VERSION 5.7 ;
  NOWIREEXTENSIONATPIN ON ;
  DIVIDERCHAR "/" ;
  BUSBITCHARS "[]" ;
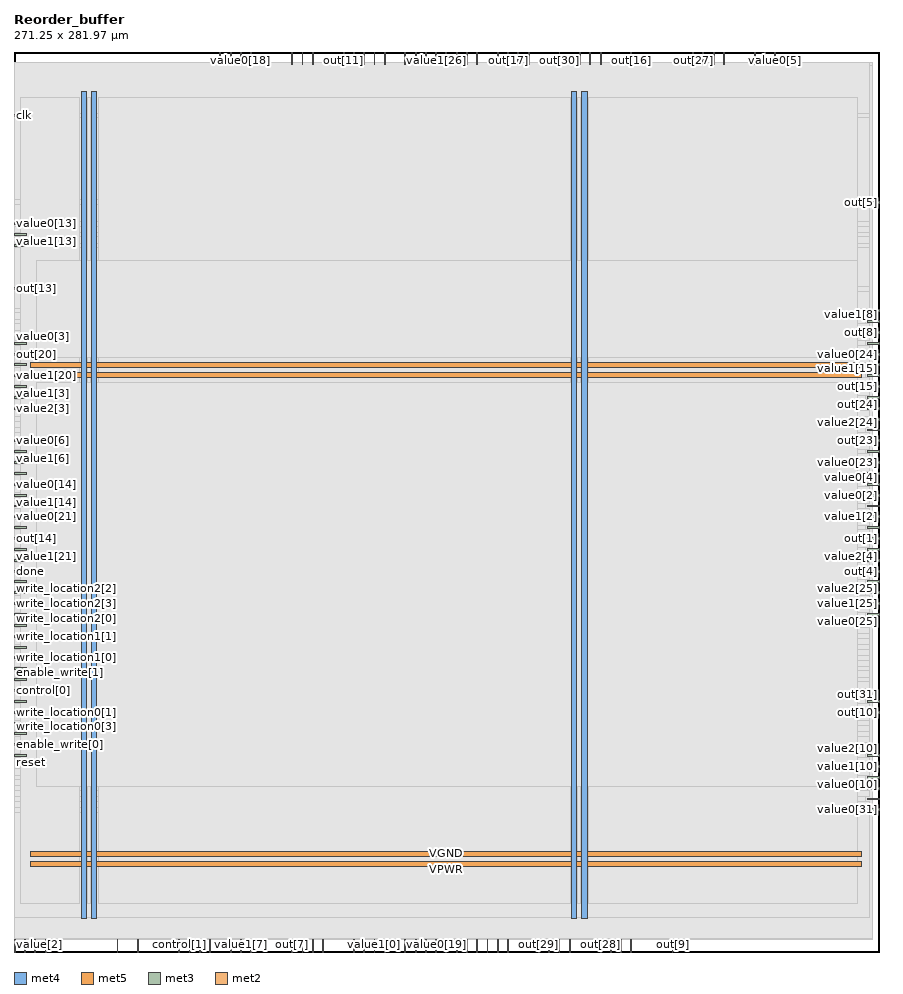
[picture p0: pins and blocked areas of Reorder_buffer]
MACRO Reorder_buffer
  CLASS BLOCK ;
  FOREIGN Reorder_buffer ;
  ORIGIN 0.000 0.000 ;
  SIZE 271.250 BY 281.970 ;
  PIN VGND
    DIRECTION INOUT ;
    USE GROUND ;
    PORT
      LAYER met4 ;
        RECT 24.340 10.640 25.940 269.520 ;
    END
    PORT
      LAYER met4 ;
        RECT 177.940 10.640 179.540 269.520 ;
    END
    PORT
      LAYER met5 ;
        RECT 5.280 30.030 265.660 31.630 ;
    END
    PORT
      LAYER met5 ;
        RECT 5.280 183.210 265.660 184.810 ;
    END
  END VGND
  PIN VPWR
    DIRECTION INOUT ;
    USE POWER ;
    PORT
      LAYER met4 ;
        RECT 21.040 10.640 22.640 269.520 ;
    END
    PORT
      LAYER met4 ;
        RECT 174.640 10.640 176.240 269.520 ;
    END
    PORT
      LAYER met5 ;
        RECT 5.280 26.730 265.660 28.330 ;
    END
    PORT
      LAYER met5 ;
        RECT 5.280 179.910 265.660 181.510 ;
    END
  END VPWR
  PIN clk
    DIRECTION INPUT ;
    USE SIGNAL ;
    ANTENNAGATEAREA 0.852000 ;
    PORT
      LAYER met3 ;
        RECT 0.000 261.840 4.000 262.440 ;
    END
  END clk
  PIN control[0]
    DIRECTION INPUT ;
    USE SIGNAL ;
    ANTENNAGATEAREA 0.196500 ;
    PORT
      LAYER met3 ;
        RECT 0.000 81.640 4.000 82.240 ;
    END
  END control[0]
  PIN control[1]
    DIRECTION INPUT ;
    USE SIGNAL ;
    ANTENNAGATEAREA 0.196500 ;
    PORT
      LAYER met2 ;
        RECT 51.610 0.000 51.890 4.000 ;
    END
  END control[1]
  PIN data_location[0]
    DIRECTION OUTPUT ;
    USE SIGNAL ;
    ANTENNADIFFAREA 0.445500 ;
    PORT
      LAYER met2 ;
        RECT 38.730 0.000 39.010 4.000 ;
    END
  END data_location[0]
  PIN data_location[1]
    DIRECTION OUTPUT ;
    USE SIGNAL ;
    ANTENNADIFFAREA 0.445500 ;
    PORT
      LAYER met2 ;
        RECT 58.050 0.000 58.330 4.000 ;
    END
  END data_location[1]
  PIN data_location[2]
    DIRECTION OUTPUT ;
    USE SIGNAL ;
    ANTENNADIFFAREA 0.445500 ;
    PORT
      LAYER met2 ;
        RECT 32.290 0.000 32.570 4.000 ;
    END
  END data_location[2]
  PIN data_location[3]
    DIRECTION OUTPUT ;
    USE SIGNAL ;
    ANTENNADIFFAREA 0.445500 ;
    PORT
      LAYER met2 ;
        RECT 61.270 0.000 61.550 4.000 ;
    END
  END data_location[3]
  PIN done
    DIRECTION OUTPUT ;
    USE SIGNAL ;
    ANTENNADIFFAREA 0.445500 ;
    PORT
      LAYER met3 ;
        RECT 0.000 119.040 4.000 119.640 ;
    END
  END done
  PIN enable_write[0]
    DIRECTION INPUT ;
    USE SIGNAL ;
    ANTENNAGATEAREA 0.196500 ;
    PORT
      LAYER met3 ;
        RECT 0.000 64.640 4.000 65.240 ;
    END
  END enable_write[0]
  PIN enable_write[1]
    DIRECTION INPUT ;
    USE SIGNAL ;
    ANTENNAGATEAREA 0.196500 ;
    PORT
      LAYER met3 ;
        RECT 0.000 85.040 4.000 85.640 ;
    END
  END enable_write[1]
  PIN enable_write[2]
    DIRECTION INPUT ;
    USE SIGNAL ;
    ANTENNAGATEAREA 0.196500 ;
    PORT
      LAYER met3 ;
        RECT 0.000 112.240 4.000 112.840 ;
    END
  END enable_write[2]
  PIN out[0]
    DIRECTION OUTPUT ;
    USE SIGNAL ;
    ANTENNADIFFAREA 0.445500 ;
    PORT
      LAYER met2 ;
        RECT 125.670 0.000 125.950 4.000 ;
    END
  END out[0]
  PIN out[10]
    DIRECTION OUTPUT ;
    USE SIGNAL ;
    ANTENNADIFFAREA 0.445500 ;
    PORT
      LAYER met3 ;
        RECT 267.250 74.840 271.250 75.440 ;
    END
  END out[10]
  PIN out[11]
    DIRECTION OUTPUT ;
    USE SIGNAL ;
    ANTENNADIFFAREA 0.445500 ;
    PORT
      LAYER met2 ;
        RECT 103.130 277.970 103.410 281.970 ;
    END
  END out[11]
  PIN out[12]
    DIRECTION OUTPUT ;
    USE SIGNAL ;
    ANTENNADIFFAREA 0.445500 ;
    PORT
      LAYER met2 ;
        RECT 122.450 277.970 122.730 281.970 ;
    END
  END out[12]
  PIN out[13]
    DIRECTION OUTPUT ;
    USE SIGNAL ;
    ANTENNADIFFAREA 0.445500 ;
    PORT
      LAYER met3 ;
        RECT 0.000 207.440 4.000 208.040 ;
    END
  END out[13]
  PIN out[14]
    DIRECTION OUTPUT ;
    USE SIGNAL ;
    ANTENNADIFFAREA 0.445500 ;
    PORT
      LAYER met3 ;
        RECT 0.000 129.240 4.000 129.840 ;
    END
  END out[14]
  PIN out[15]
    DIRECTION OUTPUT ;
    USE SIGNAL ;
    ANTENNADIFFAREA 0.445500 ;
    PORT
      LAYER met3 ;
        RECT 267.250 176.840 271.250 177.440 ;
    END
  END out[15]
  PIN out[16]
    DIRECTION OUTPUT ;
    USE SIGNAL ;
    ANTENNADIFFAREA 0.445500 ;
    PORT
      LAYER met2 ;
        RECT 193.290 277.970 193.570 281.970 ;
    END
  END out[16]
  PIN out[17]
    DIRECTION OUTPUT ;
    USE SIGNAL ;
    ANTENNADIFFAREA 0.445500 ;
    PORT
      LAYER met2 ;
        RECT 154.650 277.970 154.930 281.970 ;
    END
  END out[17]
  PIN out[18]
    DIRECTION OUTPUT ;
    USE SIGNAL ;
    ANTENNADIFFAREA 0.445500 ;
    PORT
      LAYER met2 ;
        RECT 74.150 277.970 74.430 281.970 ;
    END
  END out[18]
  PIN out[19]
    DIRECTION OUTPUT ;
    USE SIGNAL ;
    ANTENNADIFFAREA 0.445500 ;
    PORT
      LAYER met2 ;
        RECT 148.210 0.000 148.490 4.000 ;
    END
  END out[19]
  PIN out[1]
    DIRECTION OUTPUT ;
    USE SIGNAL ;
    ANTENNADIFFAREA 0.445500 ;
    PORT
      LAYER met3 ;
        RECT 267.250 129.240 271.250 129.840 ;
    END
  END out[1]
  PIN out[20]
    DIRECTION OUTPUT ;
    USE SIGNAL ;
    ANTENNADIFFAREA 0.445500 ;
    PORT
      LAYER met3 ;
        RECT 0.000 187.040 4.000 187.640 ;
    END
  END out[20]
  PIN out[21]
    DIRECTION OUTPUT ;
    USE SIGNAL ;
    ANTENNADIFFAREA 0.445500 ;
    PORT
      LAYER met3 ;
        RECT 0.000 132.640 4.000 133.240 ;
    END
  END out[21]
  PIN out[22]
    DIRECTION OUTPUT ;
    USE SIGNAL ;
    ANTENNADIFFAREA 0.445500 ;
    PORT
      LAYER met2 ;
        RECT 106.350 0.000 106.630 4.000 ;
    END
  END out[22]
  PIN out[23]
    DIRECTION OUTPUT ;
    USE SIGNAL ;
    ANTENNADIFFAREA 0.445500 ;
    PORT
      LAYER met3 ;
        RECT 267.250 159.840 271.250 160.440 ;
    END
  END out[23]
  PIN out[24]
    DIRECTION OUTPUT ;
    USE SIGNAL ;
    ANTENNADIFFAREA 0.445500 ;
    PORT
      LAYER met3 ;
        RECT 267.250 173.440 271.250 174.040 ;
    END
  END out[24]
  PIN out[25]
    DIRECTION OUTPUT ;
    USE SIGNAL ;
    ANTENNADIFFAREA 0.445500 ;
    PORT
      LAYER met3 ;
        RECT 267.250 112.240 271.250 112.840 ;
    END
  END out[25]
  PIN out[26]
    DIRECTION OUTPUT ;
    USE SIGNAL ;
    ANTENNADIFFAREA 0.445500 ;
    PORT
      LAYER met2 ;
        RECT 144.990 277.970 145.270 281.970 ;
    END
  END out[26]
  PIN out[27]
    DIRECTION OUTPUT ;
    USE SIGNAL ;
    ANTENNADIFFAREA 0.445500 ;
    PORT
      LAYER met2 ;
        RECT 212.610 277.970 212.890 281.970 ;
    END
  END out[27]
  PIN out[28]
    DIRECTION OUTPUT ;
    USE SIGNAL ;
    ANTENNADIFFAREA 0.445500 ;
    PORT
      LAYER met2 ;
        RECT 183.630 0.000 183.910 4.000 ;
    END
  END out[28]
  PIN out[29]
    DIRECTION OUTPUT ;
    USE SIGNAL ;
    ANTENNADIFFAREA 0.445500 ;
    PORT
      LAYER met2 ;
        RECT 164.310 0.000 164.590 4.000 ;
    END
  END out[29]
  PIN out[2]
    DIRECTION OUTPUT ;
    USE SIGNAL ;
    ANTENNADIFFAREA 0.445500 ;
    PORT
      LAYER met3 ;
        RECT 267.250 132.640 271.250 133.240 ;
    END
  END out[2]
  PIN out[30]
    DIRECTION OUTPUT ;
    USE SIGNAL ;
    ANTENNADIFFAREA 0.445500 ;
    PORT
      LAYER met2 ;
        RECT 170.750 277.970 171.030 281.970 ;
    END
  END out[30]
  PIN out[31]
    DIRECTION OUTPUT ;
    USE SIGNAL ;
    ANTENNADIFFAREA 0.445500 ;
    PORT
      LAYER met3 ;
        RECT 267.250 78.240 271.250 78.840 ;
    END
  END out[31]
  PIN out[3]
    DIRECTION OUTPUT ;
    USE SIGNAL ;
    ANTENNADIFFAREA 0.445500 ;
    PORT
      LAYER met2 ;
        RECT 106.350 277.970 106.630 281.970 ;
    END
  END out[3]
  PIN out[4]
    DIRECTION OUTPUT ;
    USE SIGNAL ;
    ANTENNADIFFAREA 0.445500 ;
    PORT
      LAYER met3 ;
        RECT 267.250 119.040 271.250 119.640 ;
    END
  END out[4]
  PIN out[5]
    DIRECTION OUTPUT ;
    USE SIGNAL ;
    ANTENNADIFFAREA 0.445500 ;
    PORT
      LAYER met3 ;
        RECT 267.250 234.640 271.250 235.240 ;
    END
  END out[5]
  PIN out[6]
    DIRECTION OUTPUT ;
    USE SIGNAL ;
    ANTENNADIFFAREA 0.445500 ;
    PORT
      LAYER met3 ;
        RECT 0.000 149.640 4.000 150.240 ;
    END
  END out[6]
  PIN out[7]
    DIRECTION OUTPUT ;
    USE SIGNAL ;
    ANTENNADIFFAREA 0.445500 ;
    PORT
      LAYER met2 ;
        RECT 87.030 0.000 87.310 4.000 ;
    END
  END out[7]
  PIN out[8]
    DIRECTION OUTPUT ;
    USE SIGNAL ;
    ANTENNADIFFAREA 0.445500 ;
    PORT
      LAYER met3 ;
        RECT 267.250 193.840 271.250 194.440 ;
    END
  END out[8]
  PIN out[9]
    DIRECTION OUTPUT ;
    USE SIGNAL ;
    ANTENNADIFFAREA 0.445500 ;
    PORT
      LAYER met2 ;
        RECT 206.170 0.000 206.450 4.000 ;
    END
  END out[9]
  PIN reset
    DIRECTION INPUT ;
    USE SIGNAL ;
    ANTENNAGATEAREA 0.196500 ;
    PORT
      LAYER met3 ;
        RECT 0.000 61.240 4.000 61.840 ;
    END
  END reset
  PIN success
    DIRECTION OUTPUT ;
    USE SIGNAL ;
    ANTENNADIFFAREA 0.445500 ;
    PORT
      LAYER met2 ;
        RECT 54.830 0.000 55.110 4.000 ;
    END
  END success
  PIN value0[0]
    DIRECTION INPUT ;
    USE SIGNAL ;
    ANTENNAGATEAREA 0.196500 ;
    PORT
      LAYER met2 ;
        RECT 109.570 0.000 109.850 4.000 ;
    END
  END value0[0]
  PIN value0[10]
    DIRECTION INPUT ;
    USE SIGNAL ;
    ANTENNAGATEAREA 0.196500 ;
    PORT
      LAYER met3 ;
        RECT 267.250 54.440 271.250 55.040 ;
    END
  END value0[10]
  PIN value0[11]
    DIRECTION INPUT ;
    USE SIGNAL ;
    ANTENNAGATEAREA 0.196500 ;
    PORT
      LAYER met2 ;
        RECT 90.250 277.970 90.530 281.970 ;
    END
  END value0[11]
  PIN value0[12]
    DIRECTION INPUT ;
    USE SIGNAL ;
    ANTENNAGATEAREA 0.196500 ;
    PORT
      LAYER met2 ;
        RECT 116.010 277.970 116.290 281.970 ;
    END
  END value0[12]
  PIN value0[13]
    DIRECTION INPUT ;
    USE SIGNAL ;
    ANTENNAGATEAREA 0.196500 ;
    PORT
      LAYER met3 ;
        RECT 0.000 227.840 4.000 228.440 ;
    END
  END value0[13]
  PIN value0[14]
    DIRECTION INPUT ;
    USE SIGNAL ;
    ANTENNAGATEAREA 0.196500 ;
    PORT
      LAYER met3 ;
        RECT 0.000 146.240 4.000 146.840 ;
    END
  END value0[14]
  PIN value0[15]
    DIRECTION INPUT ;
    USE SIGNAL ;
    ANTENNAGATEAREA 0.196500 ;
    PORT
      LAYER met3 ;
        RECT 267.250 183.640 271.250 184.240 ;
    END
  END value0[15]
  PIN value0[16]
    DIRECTION INPUT ;
    USE SIGNAL ;
    ANTENNAGATEAREA 0.196500 ;
    PORT
      LAYER met2 ;
        RECT 183.630 277.970 183.910 281.970 ;
    END
  END value0[16]
  PIN value0[17]
    DIRECTION INPUT ;
    USE SIGNAL ;
    ANTENNAGATEAREA 0.196500 ;
    PORT
      LAYER met2 ;
        RECT 141.770 277.970 142.050 281.970 ;
    END
  END value0[17]
  PIN value0[18]
    DIRECTION INPUT ;
    USE SIGNAL ;
    ANTENNAGATEAREA 0.196500 ;
    PORT
      LAYER met2 ;
        RECT 70.930 277.970 71.210 281.970 ;
    END
  END value0[18]
  PIN value0[19]
    DIRECTION INPUT ;
    USE SIGNAL ;
    ANTENNAGATEAREA 0.196500 ;
    PORT
      LAYER met2 ;
        RECT 132.110 0.000 132.390 4.000 ;
    END
  END value0[19]
  PIN value0[1]
    DIRECTION INPUT ;
    USE SIGNAL ;
    ANTENNAGATEAREA 0.196500 ;
    PORT
      LAYER met2 ;
        RECT 122.450 0.000 122.730 4.000 ;
    END
  END value0[1]
  PIN value0[20]
    DIRECTION INPUT ;
    USE SIGNAL ;
    ANTENNAGATEAREA 0.196500 ;
    PORT
      LAYER met3 ;
        RECT 0.000 183.640 4.000 184.240 ;
    END
  END value0[20]
  PIN value0[21]
    DIRECTION INPUT ;
    USE SIGNAL ;
    ANTENNAGATEAREA 0.196500 ;
    PORT
      LAYER met3 ;
        RECT 0.000 136.040 4.000 136.640 ;
    END
  END value0[21]
  PIN value0[22]
    DIRECTION INPUT ;
    USE SIGNAL ;
    ANTENNAGATEAREA 0.196500 ;
    PORT
      LAYER met2 ;
        RECT 90.250 0.000 90.530 4.000 ;
    END
  END value0[22]
  PIN value0[23]
    DIRECTION INPUT ;
    USE SIGNAL ;
    ANTENNAGATEAREA 0.196500 ;
    PORT
      LAYER met3 ;
        RECT 267.250 153.040 271.250 153.640 ;
    END
  END value0[23]
  PIN value0[24]
    DIRECTION INPUT ;
    USE SIGNAL ;
    ANTENNAGATEAREA 0.196500 ;
    PORT
      LAYER met3 ;
        RECT 267.250 187.040 271.250 187.640 ;
    END
  END value0[24]
  PIN value0[25]
    DIRECTION INPUT ;
    USE SIGNAL ;
    ANTENNAGATEAREA 0.196500 ;
    PORT
      LAYER met3 ;
        RECT 267.250 105.440 271.250 106.040 ;
    END
  END value0[25]
  PIN value0[26]
    DIRECTION INPUT ;
    USE SIGNAL ;
    ANTENNAGATEAREA 0.196500 ;
    PORT
      LAYER met2 ;
        RECT 128.890 277.970 129.170 281.970 ;
    END
  END value0[26]
  PIN value0[27]
    DIRECTION INPUT ;
    USE SIGNAL ;
    ANTENNAGATEAREA 0.196500 ;
    PORT
      LAYER met2 ;
        RECT 222.270 277.970 222.550 281.970 ;
    END
  END value0[27]
  PIN value0[28]
    DIRECTION INPUT ;
    USE SIGNAL ;
    ANTENNAGATEAREA 0.196500 ;
    PORT
      LAYER met2 ;
        RECT 167.530 0.000 167.810 4.000 ;
    END
  END value0[28]
  PIN value0[29]
    DIRECTION INPUT ;
    USE SIGNAL ;
    ANTENNAGATEAREA 0.196500 ;
    PORT
      LAYER met2 ;
        RECT 144.990 0.000 145.270 4.000 ;
    END
  END value0[29]
  PIN value0[2]
    DIRECTION INPUT ;
    USE SIGNAL ;
    ANTENNAGATEAREA 0.196500 ;
    PORT
      LAYER met3 ;
        RECT 267.250 142.840 271.250 143.440 ;
    END
  END value0[2]
  PIN value0[30]
    DIRECTION INPUT ;
    USE SIGNAL ;
    ANTENNAGATEAREA 0.196500 ;
    PORT
      LAYER met2 ;
        RECT 161.090 277.970 161.370 281.970 ;
    END
  END value0[30]
  PIN value0[31]
    DIRECTION INPUT ;
    USE SIGNAL ;
    ANTENNAGATEAREA 0.196500 ;
    PORT
      LAYER met3 ;
        RECT 267.250 44.240 271.250 44.840 ;
    END
  END value0[31]
  PIN value0[3]
    DIRECTION INPUT ;
    USE SIGNAL ;
    ANTENNAGATEAREA 0.196500 ;
    PORT
      LAYER met3 ;
        RECT 0.000 190.440 4.000 191.040 ;
    END
  END value0[3]
  PIN value0[4]
    DIRECTION INPUT ;
    USE SIGNAL ;
    ANTENNAGATEAREA 0.196500 ;
    PORT
      LAYER met3 ;
        RECT 267.250 146.240 271.250 146.840 ;
    END
  END value0[4]
  PIN value0[5]
    DIRECTION INPUT ;
    USE SIGNAL ;
    ANTENNAGATEAREA 0.196500 ;
    PORT
      LAYER met2 ;
        RECT 238.370 277.970 238.650 281.970 ;
    END
  END value0[5]
  PIN value0[6]
    DIRECTION INPUT ;
    USE SIGNAL ;
    ANTENNAGATEAREA 0.196500 ;
    PORT
      LAYER met3 ;
        RECT 0.000 159.840 4.000 160.440 ;
    END
  END value0[6]
  PIN value0[7]
    DIRECTION INPUT ;
    USE SIGNAL ;
    ANTENNAGATEAREA 0.196500 ;
    PORT
      LAYER met2 ;
        RECT 67.710 0.000 67.990 4.000 ;
    END
  END value0[7]
  PIN value0[8]
    DIRECTION INPUT ;
    USE SIGNAL ;
    ANTENNAGATEAREA 0.196500 ;
    PORT
      LAYER met3 ;
        RECT 267.250 190.440 271.250 191.040 ;
    END
  END value0[8]
  PIN value0[9]
    DIRECTION INPUT ;
    USE SIGNAL ;
    ANTENNAGATEAREA 0.196500 ;
    PORT
      LAYER met2 ;
        RECT 186.850 0.000 187.130 4.000 ;
    END
  END value0[9]
  PIN value1[0]
    DIRECTION INPUT ;
    USE SIGNAL ;
    ANTENNAGATEAREA 0.196500 ;
    PORT
      LAYER met2 ;
        RECT 112.790 0.000 113.070 4.000 ;
    END
  END value1[0]
  PIN value1[10]
    DIRECTION INPUT ;
    USE SIGNAL ;
    ANTENNAGATEAREA 0.196500 ;
    PORT
      LAYER met3 ;
        RECT 267.250 57.840 271.250 58.440 ;
    END
  END value1[10]
  PIN value1[11]
    DIRECTION INPUT ;
    USE SIGNAL ;
    ANTENNAGATEAREA 0.196500 ;
    PORT
      LAYER met2 ;
        RECT 87.030 277.970 87.310 281.970 ;
    END
  END value1[11]
  PIN value1[12]
    DIRECTION INPUT ;
    USE SIGNAL ;
    ANTENNAGATEAREA 0.196500 ;
    PORT
      LAYER met2 ;
        RECT 112.790 277.970 113.070 281.970 ;
    END
  END value1[12]
  PIN value1[13]
    DIRECTION INPUT ;
    USE SIGNAL ;
    ANTENNAGATEAREA 0.196500 ;
    PORT
      LAYER met3 ;
        RECT 0.000 224.440 4.000 225.040 ;
    END
  END value1[13]
  PIN value1[14]
    DIRECTION INPUT ;
    USE SIGNAL ;
    ANTENNAGATEAREA 0.196500 ;
    PORT
      LAYER met3 ;
        RECT 0.000 142.840 4.000 143.440 ;
    END
  END value1[14]
  PIN value1[15]
    DIRECTION INPUT ;
    USE SIGNAL ;
    ANTENNAGATEAREA 0.196500 ;
    PORT
      LAYER met3 ;
        RECT 267.250 180.240 271.250 180.840 ;
    END
  END value1[15]
  PIN value1[16]
    DIRECTION INPUT ;
    USE SIGNAL ;
    ANTENNAGATEAREA 0.196500 ;
    PORT
      LAYER met2 ;
        RECT 180.410 277.970 180.690 281.970 ;
    END
  END value1[16]
  PIN value1[17]
    DIRECTION INPUT ;
    USE SIGNAL ;
    ANTENNAGATEAREA 0.196500 ;
    PORT
      LAYER met2 ;
        RECT 135.330 277.970 135.610 281.970 ;
    END
  END value1[17]
  PIN value1[18]
    DIRECTION INPUT ;
    USE SIGNAL ;
    ANTENNAGATEAREA 0.196500 ;
    PORT
      LAYER met2 ;
        RECT 67.710 277.970 67.990 281.970 ;
    END
  END value1[18]
  PIN value1[19]
    DIRECTION INPUT ;
    USE SIGNAL ;
    ANTENNAGATEAREA 0.196500 ;
    PORT
      LAYER met2 ;
        RECT 135.330 0.000 135.610 4.000 ;
    END
  END value1[19]
  PIN value1[1]
    DIRECTION INPUT ;
    USE SIGNAL ;
    ANTENNAGATEAREA 0.196500 ;
    PORT
      LAYER met2 ;
        RECT 138.550 0.000 138.830 4.000 ;
    END
  END value1[1]
  PIN value1[20]
    DIRECTION INPUT ;
    USE SIGNAL ;
    ANTENNAGATEAREA 0.196500 ;
    PORT
      LAYER met3 ;
        RECT 0.000 180.240 4.000 180.840 ;
    END
  END value1[20]
  PIN value1[21]
    DIRECTION INPUT ;
    USE SIGNAL ;
    ANTENNAGATEAREA 0.196500 ;
    PORT
      LAYER met3 ;
        RECT 0.000 125.840 4.000 126.440 ;
    END
  END value1[21]
  PIN value1[22]
    DIRECTION INPUT ;
    USE SIGNAL ;
    ANTENNAGATEAREA 0.196500 ;
    PORT
      LAYER met2 ;
        RECT 93.470 0.000 93.750 4.000 ;
    END
  END value1[22]
  PIN value1[23]
    DIRECTION INPUT ;
    USE SIGNAL ;
    ANTENNAGATEAREA 0.196500 ;
    PORT
      LAYER met3 ;
        RECT 267.250 156.440 271.250 157.040 ;
    END
  END value1[23]
  PIN value1[24]
    DIRECTION INPUT ;
    USE SIGNAL ;
    ANTENNAGATEAREA 0.196500 ;
    PORT
      LAYER met3 ;
        RECT 267.250 166.640 271.250 167.240 ;
    END
  END value1[24]
  PIN value1[25]
    DIRECTION INPUT ;
    USE SIGNAL ;
    ANTENNAGATEAREA 0.196500 ;
    PORT
      LAYER met3 ;
        RECT 267.250 108.840 271.250 109.440 ;
    END
  END value1[25]
  PIN value1[26]
    DIRECTION INPUT ;
    USE SIGNAL ;
    ANTENNAGATEAREA 0.196500 ;
    PORT
      LAYER met2 ;
        RECT 132.110 277.970 132.390 281.970 ;
    END
  END value1[26]
  PIN value1[27]
    DIRECTION INPUT ;
    USE SIGNAL ;
    ANTENNAGATEAREA 0.196500 ;
    PORT
      LAYER met2 ;
        RECT 219.050 277.970 219.330 281.970 ;
    END
  END value1[27]
  PIN value1[28]
    DIRECTION INPUT ;
    USE SIGNAL ;
    ANTENNAGATEAREA 0.196500 ;
    PORT
      LAYER met2 ;
        RECT 170.750 0.000 171.030 4.000 ;
    END
  END value1[28]
  PIN value1[29]
    DIRECTION INPUT ;
    USE SIGNAL ;
    ANTENNAGATEAREA 0.196500 ;
    PORT
      LAYER met2 ;
        RECT 151.430 0.000 151.710 4.000 ;
    END
  END value1[29]
  PIN value1[2]
    DIRECTION INPUT ;
    USE SIGNAL ;
    ANTENNAGATEAREA 0.196500 ;
    PORT
      LAYER met3 ;
        RECT 267.250 136.040 271.250 136.640 ;
    END
  END value1[2]
  PIN value1[30]
    DIRECTION INPUT ;
    USE SIGNAL ;
    ANTENNAGATEAREA 0.196500 ;
    PORT
      LAYER met2 ;
        RECT 157.870 277.970 158.150 281.970 ;
    END
  END value1[30]
  PIN value1[31]
    DIRECTION INPUT ;
    USE SIGNAL ;
    ANTENNAGATEAREA 0.196500 ;
    PORT
      LAYER met3 ;
        RECT 267.250 47.640 271.250 48.240 ;
    END
  END value1[31]
  PIN value1[3]
    DIRECTION INPUT ;
    USE SIGNAL ;
    ANTENNAGATEAREA 0.196500 ;
    PORT
      LAYER met3 ;
        RECT 0.000 176.840 4.000 177.440 ;
    END
  END value1[3]
  PIN value1[4]
    DIRECTION INPUT ;
    USE SIGNAL ;
    ANTENNAGATEAREA 0.196500 ;
    PORT
      LAYER met3 ;
        RECT 267.250 122.440 271.250 123.040 ;
    END
  END value1[4]
  PIN value1[5]
    DIRECTION INPUT ;
    USE SIGNAL ;
    ANTENNAGATEAREA 0.196500 ;
    PORT
      LAYER met2 ;
        RECT 235.150 277.970 235.430 281.970 ;
    END
  END value1[5]
  PIN value1[6]
    DIRECTION INPUT ;
    USE SIGNAL ;
    ANTENNAGATEAREA 0.196500 ;
    PORT
      LAYER met3 ;
        RECT 0.000 156.440 4.000 157.040 ;
    END
  END value1[6]
  PIN value1[7]
    DIRECTION INPUT ;
    USE SIGNAL ;
    ANTENNAGATEAREA 0.196500 ;
    PORT
      LAYER met2 ;
        RECT 70.930 0.000 71.210 4.000 ;
    END
  END value1[7]
  PIN value1[8]
    DIRECTION INPUT ;
    USE SIGNAL ;
    ANTENNAGATEAREA 0.196500 ;
    PORT
      LAYER met3 ;
        RECT 267.250 197.240 271.250 197.840 ;
    END
  END value1[8]
  PIN value1[9]
    DIRECTION INPUT ;
    USE SIGNAL ;
    ANTENNAGATEAREA 0.196500 ;
    PORT
      LAYER met2 ;
        RECT 190.070 0.000 190.350 4.000 ;
    END
  END value1[9]
  PIN value2[0]
    DIRECTION INPUT ;
    USE SIGNAL ;
    ANTENNAGATEAREA 0.196500 ;
    PORT
      LAYER met2 ;
        RECT 116.010 0.000 116.290 4.000 ;
    END
  END value2[0]
  PIN value2[10]
    DIRECTION INPUT ;
    USE SIGNAL ;
    ANTENNAGATEAREA 0.196500 ;
    PORT
      LAYER met3 ;
        RECT 267.250 61.240 271.250 61.840 ;
    END
  END value2[10]
  PIN value2[11]
    DIRECTION INPUT ;
    USE SIGNAL ;
    ANTENNAGATEAREA 0.196500 ;
    PORT
      LAYER met2 ;
        RECT 93.470 277.970 93.750 281.970 ;
    END
  END value2[11]
  PIN value2[12]
    DIRECTION INPUT ;
    USE SIGNAL ;
    ANTENNAGATEAREA 0.196500 ;
    PORT
      LAYER met2 ;
        RECT 109.570 277.970 109.850 281.970 ;
    END
  END value2[12]
  PIN value2[13]
    DIRECTION INPUT ;
    USE SIGNAL ;
    ANTENNAGATEAREA 0.196500 ;
    PORT
      LAYER met3 ;
        RECT 0.000 221.040 4.000 221.640 ;
    END
  END value2[13]
  PIN value2[14]
    DIRECTION INPUT ;
    USE SIGNAL ;
    ANTENNAGATEAREA 0.196500 ;
    PORT
      LAYER met3 ;
        RECT 0.000 139.440 4.000 140.040 ;
    END
  END value2[14]
  PIN value2[15]
    DIRECTION INPUT ;
    USE SIGNAL ;
    ANTENNAGATEAREA 0.196500 ;
    PORT
      LAYER met3 ;
        RECT 267.250 170.040 271.250 170.640 ;
    END
  END value2[15]
  PIN value2[16]
    DIRECTION INPUT ;
    USE SIGNAL ;
    ANTENNAGATEAREA 0.196500 ;
    PORT
      LAYER met2 ;
        RECT 177.190 277.970 177.470 281.970 ;
    END
  END value2[16]
  PIN value2[17]
    DIRECTION INPUT ;
    USE SIGNAL ;
    ANTENNAGATEAREA 0.196500 ;
    PORT
      LAYER met2 ;
        RECT 125.670 277.970 125.950 281.970 ;
    END
  END value2[17]
  PIN value2[18]
    DIRECTION INPUT ;
    USE SIGNAL ;
    ANTENNAGATEAREA 0.196500 ;
    PORT
      LAYER met2 ;
        RECT 64.490 277.970 64.770 281.970 ;
    END
  END value2[18]
  PIN value2[19]
    DIRECTION INPUT ;
    USE SIGNAL ;
    ANTENNAGATEAREA 0.196500 ;
    PORT
      LAYER met2 ;
        RECT 128.890 0.000 129.170 4.000 ;
    END
  END value2[19]
  PIN value2[1]
    DIRECTION INPUT ;
    USE SIGNAL ;
    ANTENNAGATEAREA 0.196500 ;
    PORT
      LAYER met2 ;
        RECT 141.770 0.000 142.050 4.000 ;
    END
  END value2[1]
  PIN value2[20]
    DIRECTION INPUT ;
    USE SIGNAL ;
    ANTENNAGATEAREA 0.196500 ;
    PORT
      LAYER met3 ;
        RECT 0.000 173.440 4.000 174.040 ;
    END
  END value2[20]
  PIN value2[21]
    DIRECTION INPUT ;
    USE SIGNAL ;
    ANTENNAGATEAREA 0.196500 ;
    PORT
      LAYER met3 ;
        RECT 0.000 122.440 4.000 123.040 ;
    END
  END value2[21]
  PIN value2[22]
    DIRECTION INPUT ;
    USE SIGNAL ;
    ANTENNAGATEAREA 0.196500 ;
    PORT
      LAYER met2 ;
        RECT 96.690 0.000 96.970 4.000 ;
    END
  END value2[22]
  PIN value2[23]
    DIRECTION INPUT ;
    USE SIGNAL ;
    ANTENNAGATEAREA 0.196500 ;
    PORT
      LAYER met3 ;
        RECT 267.250 149.640 271.250 150.240 ;
    END
  END value2[23]
  PIN value2[24]
    DIRECTION INPUT ;
    USE SIGNAL ;
    ANTENNAGATEAREA 0.196500 ;
    PORT
      LAYER met3 ;
        RECT 267.250 163.240 271.250 163.840 ;
    END
  END value2[24]
  PIN value2[25]
    DIRECTION INPUT ;
    USE SIGNAL ;
    ANTENNAGATEAREA 0.196500 ;
    PORT
      LAYER met3 ;
        RECT 267.250 115.640 271.250 116.240 ;
    END
  END value2[25]
  PIN value2[26]
    DIRECTION INPUT ;
    USE SIGNAL ;
    ANTENNAGATEAREA 0.196500 ;
    PORT
      LAYER met2 ;
        RECT 138.550 277.970 138.830 281.970 ;
    END
  END value2[26]
  PIN value2[27]
    DIRECTION INPUT ;
    USE SIGNAL ;
    ANTENNAGATEAREA 0.196500 ;
    PORT
      LAYER met2 ;
        RECT 215.830 277.970 216.110 281.970 ;
    END
  END value2[27]
  PIN value2[28]
    DIRECTION INPUT ;
    USE SIGNAL ;
    ANTENNAGATEAREA 0.196500 ;
    PORT
      LAYER met2 ;
        RECT 173.970 0.000 174.250 4.000 ;
    END
  END value2[28]
  PIN value2[29]
    DIRECTION INPUT ;
    USE SIGNAL ;
    ANTENNAGATEAREA 0.196500 ;
    PORT
      LAYER met2 ;
        RECT 154.650 0.000 154.930 4.000 ;
    END
  END value2[29]
  PIN value2[2]
    DIRECTION INPUT ;
    USE SIGNAL ;
    ANTENNAGATEAREA 0.196500 ;
    PORT
      LAYER met3 ;
        RECT 267.250 139.440 271.250 140.040 ;
    END
  END value2[2]
  PIN value2[30]
    DIRECTION INPUT ;
    USE SIGNAL ;
    ANTENNAGATEAREA 0.196500 ;
    PORT
      LAYER met2 ;
        RECT 151.430 277.970 151.710 281.970 ;
    END
  END value2[30]
  PIN value2[31]
    DIRECTION INPUT ;
    USE SIGNAL ;
    ANTENNAGATEAREA 0.196500 ;
    PORT
      LAYER met3 ;
        RECT 267.250 51.040 271.250 51.640 ;
    END
  END value2[31]
  PIN value2[3]
    DIRECTION INPUT ;
    USE SIGNAL ;
    ANTENNAGATEAREA 0.196500 ;
    PORT
      LAYER met3 ;
        RECT 0.000 170.040 4.000 170.640 ;
    END
  END value2[3]
  PIN value2[4]
    DIRECTION INPUT ;
    USE SIGNAL ;
    ANTENNAGATEAREA 0.196500 ;
    PORT
      LAYER met3 ;
        RECT 267.250 125.840 271.250 126.440 ;
    END
  END value2[4]
  PIN value2[5]
    DIRECTION INPUT ;
    USE SIGNAL ;
    ANTENNAGATEAREA 0.196500 ;
    PORT
      LAYER met2 ;
        RECT 231.930 277.970 232.210 281.970 ;
    END
  END value2[5]
  PIN value2[6]
    DIRECTION INPUT ;
    USE SIGNAL ;
    ANTENNAGATEAREA 0.196500 ;
    PORT
      LAYER met3 ;
        RECT 0.000 153.040 4.000 153.640 ;
    END
  END value2[6]
  PIN value2[7]
    DIRECTION INPUT ;
    USE SIGNAL ;
    ANTENNAGATEAREA 0.196500 ;
    PORT
      LAYER met2 ;
        RECT 74.150 0.000 74.430 4.000 ;
    END
  END value2[7]
  PIN value2[8]
    DIRECTION INPUT ;
    USE SIGNAL ;
    ANTENNAGATEAREA 0.196500 ;
    PORT
      LAYER met3 ;
        RECT 267.250 200.640 271.250 201.240 ;
    END
  END value2[8]
  PIN value2[9]
    DIRECTION INPUT ;
    USE SIGNAL ;
    ANTENNAGATEAREA 0.196500 ;
    PORT
      LAYER met2 ;
        RECT 193.290 0.000 193.570 4.000 ;
    END
  END value2[9]
  PIN value[0]
    DIRECTION INPUT ;
    USE SIGNAL ;
    PORT
      LAYER met2 ;
        RECT 0.090 0.000 0.370 4.000 ;
    END
  END value[0]
  PIN value[1]
    DIRECTION INPUT ;
    USE SIGNAL ;
    PORT
      LAYER met2 ;
        RECT 3.310 0.000 3.590 4.000 ;
    END
  END value[1]
  PIN value[2]
    DIRECTION INPUT ;
    USE SIGNAL ;
    PORT
      LAYER met2 ;
        RECT 6.530 0.000 6.810 4.000 ;
    END
  END value[2]
  PIN value[3]
    DIRECTION INPUT ;
    USE SIGNAL ;
    PORT
      LAYER met2 ;
        RECT 9.750 0.000 10.030 4.000 ;
    END
  END value[3]
  PIN write_location0[0]
    DIRECTION INPUT ;
    USE SIGNAL ;
    ANTENNAGATEAREA 0.126000 ;
    PORT
      LAYER met3 ;
        RECT 0.000 78.240 4.000 78.840 ;
    END
  END write_location0[0]
  PIN write_location0[1]
    DIRECTION INPUT ;
    USE SIGNAL ;
    ANTENNAGATEAREA 0.213000 ;
    PORT
      LAYER met3 ;
        RECT 0.000 74.840 4.000 75.440 ;
    END
  END write_location0[1]
  PIN write_location0[2]
    DIRECTION INPUT ;
    USE SIGNAL ;
    ANTENNAGATEAREA 0.213000 ;
    PORT
      LAYER met3 ;
        RECT 0.000 71.440 4.000 72.040 ;
    END
  END write_location0[2]
  PIN write_location0[3]
    DIRECTION INPUT ;
    USE SIGNAL ;
    ANTENNAGATEAREA 0.196500 ;
    PORT
      LAYER met3 ;
        RECT 0.000 68.040 4.000 68.640 ;
    END
  END write_location0[3]
  PIN write_location1[0]
    DIRECTION INPUT ;
    USE SIGNAL ;
    ANTENNAGATEAREA 0.196500 ;
    PORT
      LAYER met3 ;
        RECT 0.000 91.840 4.000 92.440 ;
    END
  END write_location1[0]
  PIN write_location1[1]
    DIRECTION INPUT ;
    USE SIGNAL ;
    ANTENNAGATEAREA 0.196500 ;
    PORT
      LAYER met3 ;
        RECT 0.000 98.640 4.000 99.240 ;
    END
  END write_location1[1]
  PIN write_location1[2]
    DIRECTION INPUT ;
    USE SIGNAL ;
    ANTENNAGATEAREA 0.196500 ;
    PORT
      LAYER met3 ;
        RECT 0.000 88.440 4.000 89.040 ;
    END
  END write_location1[2]
  PIN write_location1[3]
    DIRECTION INPUT ;
    USE SIGNAL ;
    ANTENNAGATEAREA 0.196500 ;
    PORT
      LAYER met3 ;
        RECT 0.000 95.240 4.000 95.840 ;
    END
  END write_location1[3]
  PIN write_location2[0]
    DIRECTION INPUT ;
    USE SIGNAL ;
    ANTENNAGATEAREA 0.126000 ;
    PORT
      LAYER met3 ;
        RECT 0.000 102.040 4.000 102.640 ;
    END
  END write_location2[0]
  PIN write_location2[1]
    DIRECTION INPUT ;
    USE SIGNAL ;
    ANTENNAGATEAREA 0.126000 ;
    PORT
      LAYER met3 ;
        RECT 0.000 105.440 4.000 106.040 ;
    END
  END write_location2[1]
  PIN write_location2[2]
    DIRECTION INPUT ;
    USE SIGNAL ;
    ANTENNAGATEAREA 0.196500 ;
    PORT
      LAYER met3 ;
        RECT 0.000 115.640 4.000 116.240 ;
    END
  END write_location2[2]
  PIN write_location2[3]
    DIRECTION INPUT ;
    USE SIGNAL ;
    ANTENNAGATEAREA 0.196500 ;
    PORT
      LAYER met3 ;
        RECT 0.000 108.840 4.000 109.440 ;
    END
  END write_location2[3]
  OBS
      LAYER nwell ;
        RECT 5.330 10.795 265.610 269.470 ;
      LAYER li1 ;
        RECT 5.520 10.795 265.420 269.365 ;
      LAYER met1 ;
        RECT 1.450 10.640 269.030 269.920 ;
      LAYER met2 ;
        RECT 0.090 277.690 64.210 278.645 ;
        RECT 65.050 277.690 67.430 278.645 ;
        RECT 68.270 277.690 70.650 278.645 ;
        RECT 71.490 277.690 73.870 278.645 ;
        RECT 74.710 277.690 86.750 278.645 ;
        RECT 87.590 277.690 89.970 278.645 ;
        RECT 90.810 277.690 93.190 278.645 ;
        RECT 94.030 277.690 102.850 278.645 ;
        RECT 103.690 277.690 106.070 278.645 ;
        RECT 106.910 277.690 109.290 278.645 ;
        RECT 110.130 277.690 112.510 278.645 ;
        RECT 113.350 277.690 115.730 278.645 ;
        RECT 116.570 277.690 122.170 278.645 ;
        RECT 123.010 277.690 125.390 278.645 ;
        RECT 126.230 277.690 128.610 278.645 ;
        RECT 129.450 277.690 131.830 278.645 ;
        RECT 132.670 277.690 135.050 278.645 ;
        RECT 135.890 277.690 138.270 278.645 ;
        RECT 139.110 277.690 141.490 278.645 ;
        RECT 142.330 277.690 144.710 278.645 ;
        RECT 145.550 277.690 151.150 278.645 ;
        RECT 151.990 277.690 154.370 278.645 ;
        RECT 155.210 277.690 157.590 278.645 ;
        RECT 158.430 277.690 160.810 278.645 ;
        RECT 161.650 277.690 170.470 278.645 ;
        RECT 171.310 277.690 176.910 278.645 ;
        RECT 177.750 277.690 180.130 278.645 ;
        RECT 180.970 277.690 183.350 278.645 ;
        RECT 184.190 277.690 193.010 278.645 ;
        RECT 193.850 277.690 212.330 278.645 ;
        RECT 213.170 277.690 215.550 278.645 ;
        RECT 216.390 277.690 218.770 278.645 ;
        RECT 219.610 277.690 221.990 278.645 ;
        RECT 222.830 277.690 231.650 278.645 ;
        RECT 232.490 277.690 234.870 278.645 ;
        RECT 235.710 277.690 238.090 278.645 ;
        RECT 238.930 277.690 269.000 278.645 ;
        RECT 0.090 4.280 269.000 277.690 ;
        RECT 0.650 4.000 3.030 4.280 ;
        RECT 3.870 4.000 6.250 4.280 ;
        RECT 7.090 4.000 9.470 4.280 ;
        RECT 10.310 4.000 32.010 4.280 ;
        RECT 32.850 4.000 38.450 4.280 ;
        RECT 39.290 4.000 51.330 4.280 ;
        RECT 52.170 4.000 54.550 4.280 ;
        RECT 55.390 4.000 57.770 4.280 ;
        RECT 58.610 4.000 60.990 4.280 ;
        RECT 61.830 4.000 67.430 4.280 ;
        RECT 68.270 4.000 70.650 4.280 ;
        RECT 71.490 4.000 73.870 4.280 ;
        RECT 74.710 4.000 86.750 4.280 ;
        RECT 87.590 4.000 89.970 4.280 ;
        RECT 90.810 4.000 93.190 4.280 ;
        RECT 94.030 4.000 96.410 4.280 ;
        RECT 97.250 4.000 106.070 4.280 ;
        RECT 106.910 4.000 109.290 4.280 ;
        RECT 110.130 4.000 112.510 4.280 ;
        RECT 113.350 4.000 115.730 4.280 ;
        RECT 116.570 4.000 122.170 4.280 ;
        RECT 123.010 4.000 125.390 4.280 ;
        RECT 126.230 4.000 128.610 4.280 ;
        RECT 129.450 4.000 131.830 4.280 ;
        RECT 132.670 4.000 135.050 4.280 ;
        RECT 135.890 4.000 138.270 4.280 ;
        RECT 139.110 4.000 141.490 4.280 ;
        RECT 142.330 4.000 144.710 4.280 ;
        RECT 145.550 4.000 147.930 4.280 ;
        RECT 148.770 4.000 151.150 4.280 ;
        RECT 151.990 4.000 154.370 4.280 ;
        RECT 155.210 4.000 164.030 4.280 ;
        RECT 164.870 4.000 167.250 4.280 ;
        RECT 168.090 4.000 170.470 4.280 ;
        RECT 171.310 4.000 173.690 4.280 ;
        RECT 174.530 4.000 183.350 4.280 ;
        RECT 184.190 4.000 186.570 4.280 ;
        RECT 187.410 4.000 189.790 4.280 ;
        RECT 190.630 4.000 193.010 4.280 ;
        RECT 193.850 4.000 205.890 4.280 ;
        RECT 206.730 4.000 269.000 4.280 ;
      LAYER met3 ;
        RECT 0.065 262.840 268.115 278.625 ;
        RECT 4.400 261.440 268.115 262.840 ;
        RECT 0.065 235.640 268.115 261.440 ;
        RECT 0.065 234.240 266.850 235.640 ;
        RECT 0.065 228.840 268.115 234.240 ;
        RECT 4.400 227.440 268.115 228.840 ;
        RECT 0.065 225.440 268.115 227.440 ;
        RECT 4.400 224.040 268.115 225.440 ;
        RECT 0.065 222.040 268.115 224.040 ;
        RECT 4.400 220.640 268.115 222.040 ;
        RECT 0.065 208.440 268.115 220.640 ;
        RECT 4.400 207.040 268.115 208.440 ;
        RECT 0.065 201.640 268.115 207.040 ;
        RECT 0.065 200.240 266.850 201.640 ;
        RECT 0.065 198.240 268.115 200.240 ;
        RECT 0.065 196.840 266.850 198.240 ;
        RECT 0.065 194.840 268.115 196.840 ;
        RECT 0.065 193.440 266.850 194.840 ;
        RECT 0.065 191.440 268.115 193.440 ;
        RECT 4.400 190.040 266.850 191.440 ;
        RECT 0.065 188.040 268.115 190.040 ;
        RECT 4.400 186.640 266.850 188.040 ;
        RECT 0.065 184.640 268.115 186.640 ;
        RECT 4.400 183.240 266.850 184.640 ;
        RECT 0.065 181.240 268.115 183.240 ;
        RECT 4.400 179.840 266.850 181.240 ;
        RECT 0.065 177.840 268.115 179.840 ;
        RECT 4.400 176.440 266.850 177.840 ;
        RECT 0.065 174.440 268.115 176.440 ;
        RECT 4.400 173.040 266.850 174.440 ;
        RECT 0.065 171.040 268.115 173.040 ;
        RECT 4.400 169.640 266.850 171.040 ;
        RECT 0.065 167.640 268.115 169.640 ;
        RECT 0.065 166.240 266.850 167.640 ;
        RECT 0.065 164.240 268.115 166.240 ;
        RECT 0.065 162.840 266.850 164.240 ;
        RECT 0.065 160.840 268.115 162.840 ;
        RECT 4.400 159.440 266.850 160.840 ;
        RECT 0.065 157.440 268.115 159.440 ;
        RECT 4.400 156.040 266.850 157.440 ;
        RECT 0.065 154.040 268.115 156.040 ;
        RECT 4.400 152.640 266.850 154.040 ;
        RECT 0.065 150.640 268.115 152.640 ;
        RECT 4.400 149.240 266.850 150.640 ;
        RECT 0.065 147.240 268.115 149.240 ;
        RECT 4.400 145.840 266.850 147.240 ;
        RECT 0.065 143.840 268.115 145.840 ;
        RECT 4.400 142.440 266.850 143.840 ;
        RECT 0.065 140.440 268.115 142.440 ;
        RECT 4.400 139.040 266.850 140.440 ;
        RECT 0.065 137.040 268.115 139.040 ;
        RECT 4.400 135.640 266.850 137.040 ;
        RECT 0.065 133.640 268.115 135.640 ;
        RECT 4.400 132.240 266.850 133.640 ;
        RECT 0.065 130.240 268.115 132.240 ;
        RECT 4.400 128.840 266.850 130.240 ;
        RECT 0.065 126.840 268.115 128.840 ;
        RECT 4.400 125.440 266.850 126.840 ;
        RECT 0.065 123.440 268.115 125.440 ;
        RECT 4.400 122.040 266.850 123.440 ;
        RECT 0.065 120.040 268.115 122.040 ;
        RECT 4.400 118.640 266.850 120.040 ;
        RECT 0.065 116.640 268.115 118.640 ;
        RECT 4.400 115.240 266.850 116.640 ;
        RECT 0.065 113.240 268.115 115.240 ;
        RECT 4.400 111.840 266.850 113.240 ;
        RECT 0.065 109.840 268.115 111.840 ;
        RECT 4.400 108.440 266.850 109.840 ;
        RECT 0.065 106.440 268.115 108.440 ;
        RECT 4.400 105.040 266.850 106.440 ;
        RECT 0.065 103.040 268.115 105.040 ;
        RECT 4.400 101.640 268.115 103.040 ;
        RECT 0.065 99.640 268.115 101.640 ;
        RECT 4.400 98.240 268.115 99.640 ;
        RECT 0.065 96.240 268.115 98.240 ;
        RECT 4.400 94.840 268.115 96.240 ;
        RECT 0.065 92.840 268.115 94.840 ;
        RECT 4.400 91.440 268.115 92.840 ;
        RECT 0.065 89.440 268.115 91.440 ;
        RECT 4.400 88.040 268.115 89.440 ;
        RECT 0.065 86.040 268.115 88.040 ;
        RECT 4.400 84.640 268.115 86.040 ;
        RECT 0.065 82.640 268.115 84.640 ;
        RECT 4.400 81.240 268.115 82.640 ;
        RECT 0.065 79.240 268.115 81.240 ;
        RECT 4.400 77.840 266.850 79.240 ;
        RECT 0.065 75.840 268.115 77.840 ;
        RECT 4.400 74.440 266.850 75.840 ;
        RECT 0.065 72.440 268.115 74.440 ;
        RECT 4.400 71.040 268.115 72.440 ;
        RECT 0.065 69.040 268.115 71.040 ;
        RECT 4.400 67.640 268.115 69.040 ;
        RECT 0.065 65.640 268.115 67.640 ;
        RECT 4.400 64.240 268.115 65.640 ;
        RECT 0.065 62.240 268.115 64.240 ;
        RECT 4.400 60.840 266.850 62.240 ;
        RECT 0.065 58.840 268.115 60.840 ;
        RECT 0.065 57.440 266.850 58.840 ;
        RECT 0.065 55.440 268.115 57.440 ;
        RECT 0.065 54.040 266.850 55.440 ;
        RECT 0.065 52.040 268.115 54.040 ;
        RECT 0.065 50.640 266.850 52.040 ;
        RECT 0.065 48.640 268.115 50.640 ;
        RECT 0.065 47.240 266.850 48.640 ;
        RECT 0.065 45.240 268.115 47.240 ;
        RECT 0.065 43.840 266.850 45.240 ;
        RECT 0.065 10.715 268.115 43.840 ;
      LAYER met4 ;
        RECT 2.135 15.135 20.640 267.745 ;
        RECT 23.040 15.135 23.940 267.745 ;
        RECT 26.340 15.135 174.240 267.745 ;
        RECT 176.640 15.135 177.540 267.745 ;
        RECT 179.940 15.135 264.170 267.745 ;
      LAYER met5 ;
        RECT 7.020 186.410 264.380 216.700 ;
        RECT 7.020 51.900 264.380 178.310 ;
  END
END Reorder_buffer
END LIBRARY

